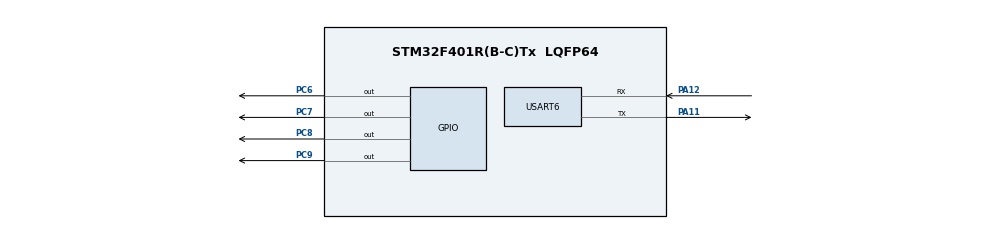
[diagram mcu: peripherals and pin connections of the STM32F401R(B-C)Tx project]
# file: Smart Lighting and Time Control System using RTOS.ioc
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Mcu.Family=STM32F4
Mcu.Name=STM32F401R(B-C)Tx
Mcu.Package=LQFP64
NVIC.PriorityGroup=NVIC_PRIORITYGROUP_4
NVIC.TIM2_IRQn=true\:15\:0\:false\:false\:true\:false\:true\:true
NVIC.TimeBase=TIM2_IRQn
NVIC.TimeBaseIP=TIM2
NVIC.USART6_IRQn=true\:8\:0\:true\:false\:true\:true\:true\:true
PA11.Mode=Asynchronous
PA11.Signal=USART6_TX
PA12.Mode=Asynchronous
PA12.Signal=USART6_RX
PA13.Mode=Serial_Wire
PA13.Signal=SYS_JTMS-SWDIO
PA14.Mode=Serial_Wire
PA14.Signal=SYS_JTCK-SWCLK
PC6.Signal=GPIO_Output
PC7.Signal=GPIO_Output
PC8.Signal=GPIO_Output
PC9.Signal=GPIO_Output
ProjectManager.HeapSize=0x200
ProjectManager.StackSize=0x400
ProjectManager.TargetToolchain=STM32CubeIDE
RCC.48MHZClocksFreq_Value=42000000
RCC.AHBFreq_Value=84000000
RCC.APB1CLKDivider=RCC_HCLK_DIV4
RCC.APB1Freq_Value=21000000
RCC.APB1TimFreq_Value=42000000
RCC.APB2Freq_Value=84000000
RCC.APB2TimFreq_Value=84000000
RCC.CortexFreq_Value=84000000
RCC.HCLKFreq_Value=84000000
RCC.HSE_VALUE=25000000
RCC.HSI_VALUE=16000000
RCC.LSE_VALUE=32768
RCC.PLLM=8
RCC.PLLN=84
RCC.SYSCLKFreq_VALUE=84000000
RCC.SYSCLKSource=RCC_SYSCLKSOURCE_PLLCLK
RCC.VCOOutputFreq_Value=168000000
USART6.VirtualMode=VM_ASYNC
VP_RTC_VS_RTC_Activate.Mode=RTC_Enabled
VP_SYS_VS_tim2.Mode=TIM2
board=custom

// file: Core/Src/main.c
/* USER CODE BEGIN Header */
/**
  ******************************************************************************
  * @file           : main.c
  * @brief          : Main program body
  ******************************************************************************
  * @attention
  *
  * Copyright (c) 2025 STMicroelectronics.
  * All rights reserved.
  *
  * This software is licensed under terms that can be found in the LICENSE file
  * in the root directory of this software component.
  * If no LICENSE file comes with this software, it is provided AS-IS.
  *
  ******************************************************************************
  */
/* USER CODE END Header */
#include "main.h"

RTC_HandleTypeDef hrtc;

UART_HandleTypeDef huart6;

void SystemClock_Config(void);
static void MX_GPIO_Init(void);
static void MX_RTC_Init(void);
static void MX_USART6_UART_Init(void);

/* USER CODE BEGIN PFP */

void MenuTask(void * pvParameters);
void CMDTask(void * pvParameters);
void LedTask(void * pvParameters);
void RTCTask(void * pvParameters);
void PrintTask(void * pvParameters);

/* USER CODE END PFP */

/* USER CODE BEGIN 0 */
TaskHandle_t HandleMenuTask;
TaskHandle_t HandleCMDTask;
TaskHandle_t HandleLedTask;
TaskHandle_t HandleRTCTask;
TaskHandle_t HandlePrintTask;

QueueHandle_t Q_Print;
QueueHandle_t Q_Data;

State_t Current_State;

volatile char UserData;

TimerHandle_t HandleLedTimer[4];
/* USER CODE END 0 */

int main(void)
{

  /* USER CODE BEGIN 1 */

BaseType_t Local_State;
uint8_t Local_u8Count;

  /* USER CODE END 1 */

  //vInitPrioGroupValue();

  /* MCU Configuration--------------------------------------------------------*/

  /* Reset of all peripherals, Initializes the Flash interface and the Systick. */
  HAL_Init();

  /* Configure the system clock */
  SystemClock_Config();

  /* USER CODE BEGIN SysInit */
  //SEGGER_SYSVIEW_Conf();
  // SEGGER_SYSVIEW_Start();
  /* USER CODE END SysInit */

  /* Initialize all configured peripherals */
  MX_GPIO_Init();
  MX_RTC_Init();
  MX_USART6_UART_Init();
  /* USER CODE BEGIN 2 */

  /* enable cycle counter feature of the processor */
  //DWT_CTRL |= 1;

  //SEGGER_UART_init(500000);
  //SEGGER_SYSVIEW_Conf();
  //SEGGER_SYSVIEW_Start();

  Local_State = xTaskCreate(MenuTask, "MenuTask", 200,NULL, 2,&HandleMenuTask);
  configASSERT(Local_State==pdPASS);

  Local_State = xTaskCreate(CMDTask, "CMDTask", 200,NULL, 2,&HandleCMDTask);
  configASSERT(Local_State==pdPASS);

  Local_State = xTaskCreate(LedTask, "LedTask", 200,NULL, 2,&HandleLedTask);
  configASSERT(Local_State==pdPASS);

  Local_State = xTaskCreate(RTCTask, "RTCTask", 200,NULL, 2,&HandleRTCTask);
  configASSERT(Local_State==pdPASS);

  Local_State = xTaskCreate(PrintTask, "PrintTask", 200,NULL, 2,&HandlePrintTask);
  configASSERT(Local_State==pdPASS);

  Q_Print = xQueueCreate(10,sizeof(uint32_t));
  configASSERT(Q_Print!=NULL);

  Q_Data = xQueueCreate(10,sizeof(char));
  configASSERT(Q_Data!=NULL);

  for(Local_u8Count=0; Local_u8Count<4; Local_u8Count++)
  {
	  HandleLedTimer[Local_u8Count] = xTimerCreate("LedTimer", pdMS_TO_TICKS(500), pdTRUE, (void*)(Local_u8Count+1),LedEffectCallBackFun);
  }

  /* enable uart receving in interrupt mode */
  HAL_UART_Receive_IT(&huart6,(uint8_t *)&UserData, 1);

  vTaskStartScheduler();

  /* USER CODE END 2 */
  /* Infinite loop */
  while (1)
  {

  }
}

void SystemClock_Config(void)
{
  RCC_OscInitTypeDef RCC_OscInitStruct = {0};
  RCC_ClkInitTypeDef RCC_ClkInitStruct = {0};

  /** Configure the main internal regulator output voltage
  */
  __HAL_RCC_PWR_CLK_ENABLE();
  __HAL_PWR_VOLTAGESCALING_CONFIG(PWR_REGULATOR_VOLTAGE_SCALE2);

  /** Initializes the RCC Oscillators according to the specified parameters
  * in the RCC_OscInitTypeDef structure.
  */
  RCC_OscInitStruct.OscillatorType = RCC_OSCILLATORTYPE_HSI|RCC_OSCILLATORTYPE_LSI;
  RCC_OscInitStruct.HSIState = RCC_HSI_ON;
  RCC_OscInitStruct.HSICalibrationValue = RCC_HSICALIBRATION_DEFAULT;
  RCC_OscInitStruct.LSIState = RCC_LSI_ON;
  RCC_OscInitStruct.PLL.PLLState = RCC_PLL_NONE;
  if (HAL_RCC_OscConfig(&RCC_OscInitStruct) != HAL_OK)
  {
    Error_Handler();
  }

  /** Initializes the CPU, AHB and APB buses clocks
  */
  RCC_ClkInitStruct.ClockType = RCC_CLOCKTYPE_HCLK|RCC_CLOCKTYPE_SYSCLK
                              |RCC_CLOCKTYPE_PCLK1|RCC_CLOCKTYPE_PCLK2;
  RCC_ClkInitStruct.SYSCLKSource = RCC_SYSCLKSOURCE_HSI;
  RCC_ClkInitStruct.AHBCLKDivider = RCC_SYSCLK_DIV1;
  RCC_ClkInitStruct.APB1CLKDivider = RCC_HCLK_DIV1;
  RCC_ClkInitStruct.APB2CLKDivider = RCC_HCLK_DIV1;

  if (HAL_RCC_ClockConfig(&RCC_ClkInitStruct, FLASH_LATENCY_0) != HAL_OK)
  {
    Error_Handler();
  }
}

static void MX_RTC_Init(void)
{

  /** Initialize RTC Only
  */
  hrtc.Instance = RTC;
  hrtc.Init.HourFormat = RTC_HOURFORMAT_24;
  hrtc.Init.AsynchPrediv = 127;
  hrtc.Init.SynchPrediv = 255;
  hrtc.Init.OutPut = RTC_OUTPUT_DISABLE;
  hrtc.Init.OutPutPolarity = RTC_OUTPUT_POLARITY_HIGH;
  hrtc.Init.OutPutType = RTC_OUTPUT_TYPE_OPENDRAIN;
  if (HAL_RTC_Init(&hrtc) != HAL_OK)
  {
    Error_Handler();
  }

}

static void MX_USART6_UART_Init(void)
{

  huart6.Instance = USART6;
  huart6.Init.BaudRate = 115200;
  huart6.Init.WordLength = UART_WORDLENGTH_8B;
  huart6.Init.StopBits = UART_STOPBITS_1;
  huart6.Init.Parity = UART_PARITY_NONE;
  huart6.Init.Mode = UART_MODE_TX_RX;
  huart6.Init.HwFlowCtl = UART_HWCONTROL_NONE;
  huart6.Init.OverSampling = UART_OVERSAMPLING_16;
  if (HAL_UART_Init(&huart6) != HAL_OK)
  {
    Error_Handler();
  }

}

static void MX_GPIO_Init(void)
{
  GPIO_InitTypeDef GPIO_InitStruct = {0};

  /* GPIO Ports Clock Enable */
  __HAL_RCC_GPIOC_CLK_ENABLE();
  __HAL_RCC_GPIOA_CLK_ENABLE();

  /*Configure GPIO pin Output Level */
  HAL_GPIO_WritePin(GPIOC, GPIO_PIN_6|GPIO_PIN_7|GPIO_PIN_8|GPIO_PIN_9, GPIO_PIN_RESET);

  /*Configure GPIO pins : PC6 PC7 PC8 PC9 */
  GPIO_InitStruct.Pin = GPIO_PIN_6|GPIO_PIN_7|GPIO_PIN_8|GPIO_PIN_9;
  GPIO_InitStruct.Mode = GPIO_MODE_OUTPUT_PP;
  GPIO_InitStruct.Pull = GPIO_NOPULL;
  GPIO_InitStruct.Speed = GPIO_SPEED_FREQ_LOW;
  HAL_GPIO_Init(GPIOC, &GPIO_InitStruct);

}

void HAL_TIM_PeriodElapsedCallback(TIM_HandleTypeDef *htim)
{
  if (htim->Instance == TIM2) {
    HAL_IncTick();
  }
}

void Error_Handler(void)
{
  __disable_irq();
  while (1)
  {
  }
}
